VERSION 5.7 ;
  NOWIREEXTENSIONATPIN ON ;
  DIVIDERCHAR "/" ;
  BUSBITCHARS "[]" ;
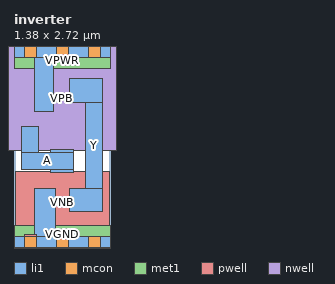
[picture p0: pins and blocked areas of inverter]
MACRO inverter
  CLASS BLOCK ;
  FOREIGN inverter ;
  ORIGIN 0.000 0.000 ;
  SIZE 1.380 BY 2.720 ;
  PIN VGND
    DIRECTION INOUT ;
    USE GROUND ;
    SHAPE ABUTMENT ;
    PORT
      LAYER li1 ;
        RECT 0.290 0.085 0.590 0.760 ;
        RECT 0.000 -0.085 1.380 0.085 ;
      LAYER mcon ;
        RECT 0.145 -0.085 0.315 0.085 ;
        RECT 0.605 -0.085 0.775 0.085 ;
        RECT 1.065 -0.085 1.235 0.085 ;
      LAYER met1 ;
        RECT 0.000 -0.240 1.380 0.240 ;
    END
  END VGND
  PIN VNB
    DIRECTION INOUT ;
    USE GROUND ;
    PORT
      LAYER pwell ;
        RECT 0.015 0.105 1.365 1.015 ;
        RECT 0.145 -0.085 0.315 0.105 ;
    END
  END VNB
  PIN VPB
    DIRECTION INOUT ;
    USE POWER ;
    PORT
      LAYER nwell ;
        RECT -0.190 1.305 1.570 2.910 ;
    END
  END VPB
  PIN VPWR
    DIRECTION INOUT ;
    USE POWER ;
    SHAPE ABUTMENT ;
    PORT
      LAYER li1 ;
        RECT 0.000 2.635 1.380 2.805 ;
        RECT 0.290 1.870 0.565 2.635 ;
      LAYER mcon ;
        RECT 0.145 2.635 0.315 2.805 ;
        RECT 0.605 2.635 0.775 2.805 ;
        RECT 1.065 2.635 1.235 2.805 ;
      LAYER met1 ;
        RECT 0.000 2.480 1.380 2.960 ;
    END
  END VPWR
  PIN Y
    DIRECTION OUTPUT ;
    USE SIGNAL ;
    ANTENNADIFFAREA 0.437125 ;
    PORT
      LAYER li1 ;
        RECT 0.790 2.000 1.270 2.340 ;
        RECT 1.025 0.760 1.270 2.000 ;
        RECT 0.790 0.430 1.270 0.760 ;
    END
  END Y
  PIN A
    DIRECTION INPUT ;
    USE SIGNAL ;
    ANTENNAGATEAREA 0.201750 ;
    PORT
      LAYER li1 ;
        RECT 0.110 1.285 0.350 1.650 ;
        RECT 0.520 1.285 0.855 1.330 ;
        RECT 0.110 1.045 0.855 1.285 ;
        RECT 0.525 1.000 0.855 1.045 ;
    END
  END A
END inverter
END LIBRARY

